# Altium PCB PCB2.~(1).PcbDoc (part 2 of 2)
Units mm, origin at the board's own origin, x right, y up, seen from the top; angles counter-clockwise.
Board outline 200 x 180 mm, 2 copper layers (Top Layer, Bottom Layer); 324 components, 291 nets, 661 pads, 0 vias.

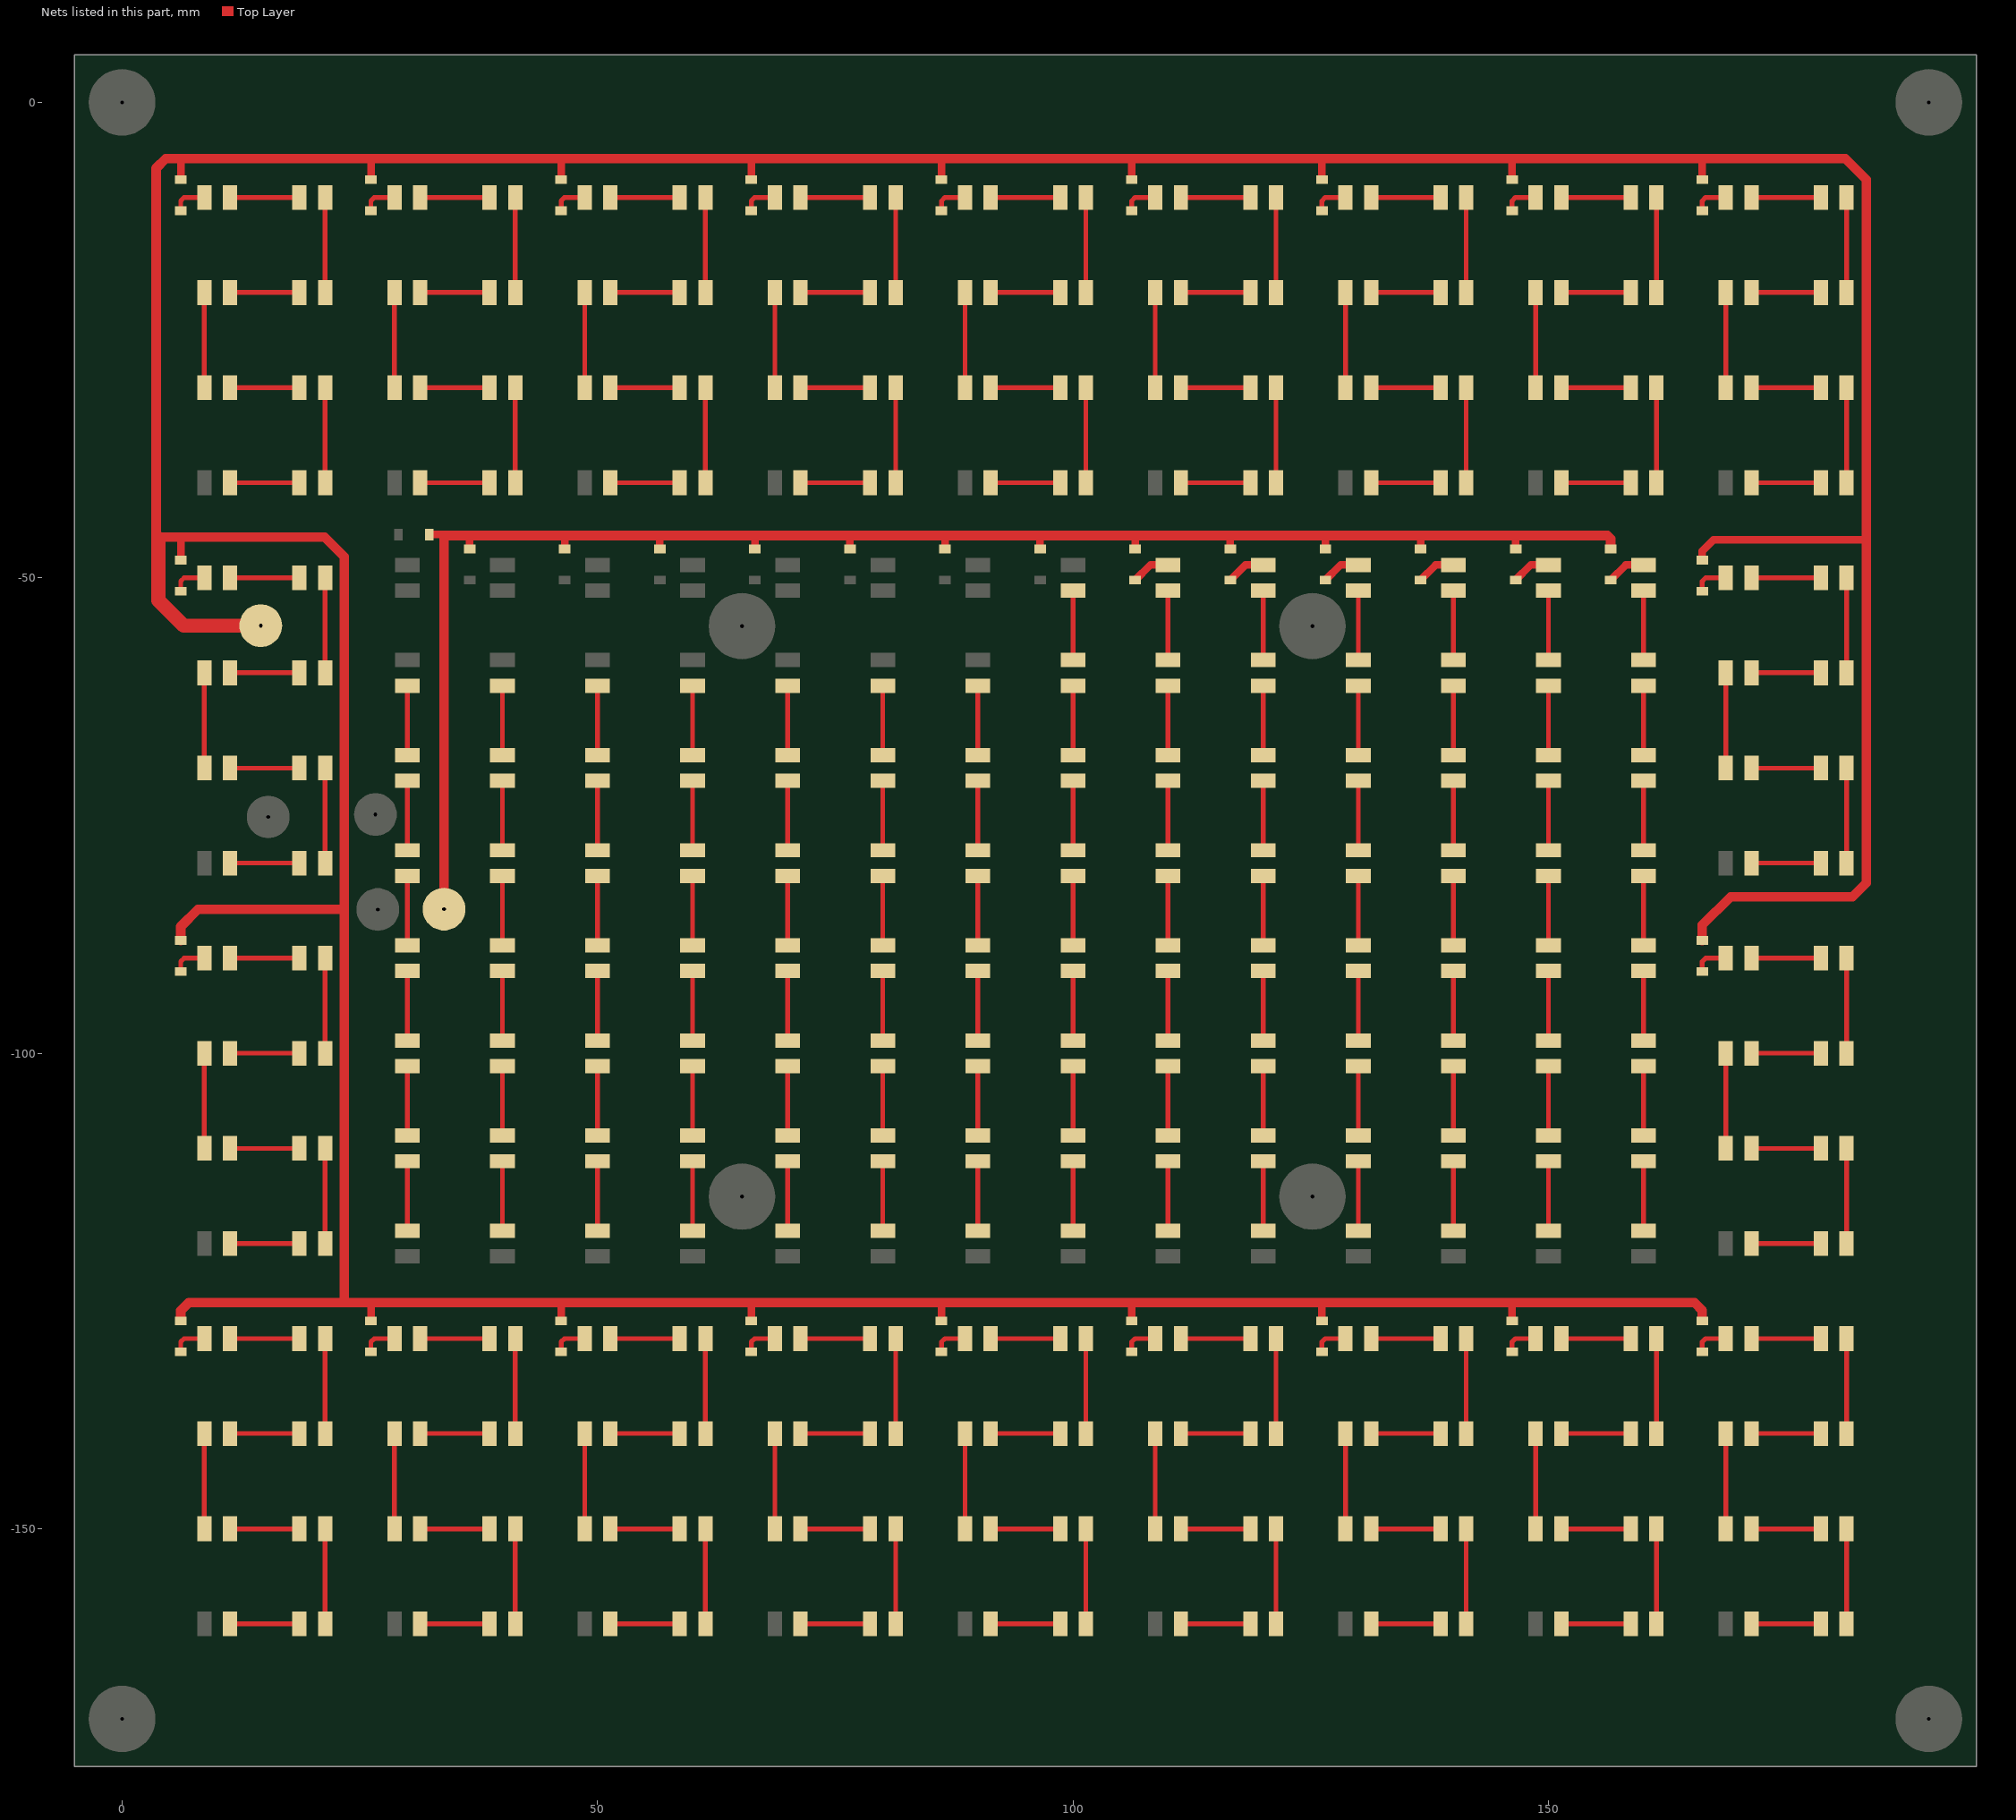
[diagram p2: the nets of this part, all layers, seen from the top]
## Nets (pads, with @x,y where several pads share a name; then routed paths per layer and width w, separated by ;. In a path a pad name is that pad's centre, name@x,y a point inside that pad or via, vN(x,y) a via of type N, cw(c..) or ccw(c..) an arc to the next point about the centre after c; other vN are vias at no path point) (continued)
NetD1_8_2: D1_8.2 D2_8.1 | length 7.3
  Top Layer w0.5: D2_8.1@100,-58.65 99.996,-58.65 99.996,-51.35 D1_8.2@100,-51.35
NetD1_9_1: D1_9.1 DR1_9.K | length 4.3
  Top Layer w0.8: DR1_9.K@106.546,-50.238 108.13,-48.654 D1_9.1@110.178,-48.654
NetD1_9_2: D1_9.2 D2_9.1 | length 7.3
  Top Layer w0.5: D2_9.1@110,-58.65 109.996,-58.65 109.996,-51.35 D1_9.2@110,-51.35
NetD1_10_1: D1_10.1 DR1_10.K | length 4.3
  Top Layer w0.8: DR1_10.K@116.546,-50.238 118.13,-48.654 D1_10.1@120.178,-48.654
NetD1_10_2: D1_10.2 D2_10.1 | length 7.3
  Top Layer w0.5: D2_10.1@120,-58.65 119.996,-58.65 119.996,-51.35 D1_10.2@120,-51.35
NetD1_11_1: D1_11.1 DR1_11.K | length 4.3
  Top Layer w0.8: DR1_11.K@126.546,-50.238 128.13,-48.654 D1_11.1@130.178,-48.654
NetD1_11_2: D1_11.2 D2_11.1 | length 7.3
  Top Layer w0.5: D2_11.1@130,-58.65 129.996,-58.65 129.996,-51.35 D1_11.2@130,-51.35
NetD1_12_1: D1_12.1 DR1_12.K | length 4.3
  Top Layer w0.8: DR1_12.K@136.546,-50.238 138.13,-48.654 D1_12.1@140.178,-48.654
NetD1_12_2: D1_12.2 D2_12.1 | length 7.3
  Top Layer w0.5: D2_12.1@140,-58.65 139.996,-58.65 139.996,-51.35 D1_12.2@140,-51.35
NetD1_13_1: D1_13.1 DR1_13.K | length 4.3
  Top Layer w0.8: DR1_13.K@146.546,-50.238 148.13,-48.654 D1_13.1@150.178,-48.654
NetD1_13_2: D1_13.2 D2_13.1 | length 7.3
  Top Layer w0.5: D2_13.1@150,-58.65 149.996,-58.65 149.996,-51.35 D1_13.2@150,-51.35
NetD1_14_1: D1_14.1 DR1_14.K | length 4.3
  Top Layer w0.8: DR1_14.K@156.546,-50.238 158.13,-48.654 D1_14.1@160.178,-48.654
NetD1_14_2: D1_14.2 D2_14.1 | length 7.3
  Top Layer w0.5: D2_14.1@160,-58.65 159.996,-58.65 159.996,-51.35 D1_14.2@160,-51.35
NetD1_15_1: D1_15.1 DR1_15.K | length 3.7
  Top Layer w0.5: DR1_15.K@6.175,-11.401 6.175,-10.351 6.525,-10 D1_15.1@8.65,-10
NetD1_15_2: D1_15.2 D2_15.1 | length 7.3
  Top Layer w0.5: D1_15.2@11.35,-10 D2_15.1@18.65,-10
NetD1_16_1: D1_16.1 DR1_16.K | length 3.7
  Top Layer w0.5: DR1_16.K@6.175,-51.401 6.175,-50.351 6.525,-50 D1_16.1@8.65,-50
NetD1_16_2: D1_16.2 D2_16.1 | length 7.3
  Top Layer w0.5: D1_16.2@11.35,-50 D2_16.1@18.65,-50
NetD1_17_1: D1_17.1 DR1_17.K | length 3.7
  Top Layer w0.5: DR1_17.K@6.175,-91.401 6.175,-90.351 6.525,-90 D1_17.1@8.65,-90
NetD1_17_2: D1_17.2 D2_17.1 | length 7.3
  Top Layer w0.5: D1_17.2@11.35,-90 D2_17.1@18.65,-90
NetD1_18_1: D1_18.1 DR1_18.K | length 3.7
  Top Layer w0.5: DR1_18.K@6.175,-131.401 6.175,-130.351 6.525,-130 D1_18.1@8.65,-130
NetD1_18_2: D1_18.2 D2_18.1 | length 7.3
  Top Layer w0.5: D1_18.2@11.35,-130 D2_18.1@18.65,-130
NetD1_19_1: D1_19.1 DR1_19.K | length 3.7
  Top Layer w0.5: DR1_19.K@26.175,-11.401 26.175,-10.351 26.525,-10 D1_19.1@28.65,-10
NetD1_19_2: D1_19.2 D2_19.1 | length 7.3
  Top Layer w0.5: D1_19.2@31.35,-10 D2_19.1@38.65,-10
NetD1_20_1: D1_20.1 DR1_20.K | length 3.7
  Top Layer w0.5: DR1_20.K@46.175,-11.401 46.175,-10.351 46.525,-10 D1_20.1@48.65,-10
NetD1_20_2: D1_20.2 D2_20.1 | length 7.3
  Top Layer w0.5: D1_20.2@51.35,-10 D2_20.1@58.65,-10
NetD1_21_1: D1_21.1 DR1_21.K | length 3.7
  Top Layer w0.5: DR1_21.K@66.175,-11.401 66.175,-10.351 66.525,-10 D1_21.1@68.65,-10
NetD1_21_2: D1_21.2 D2_21.1 | length 7.3
  Top Layer w0.5: D1_21.2@71.35,-10 D2_21.1@78.65,-10
NetD1_22_1: D1_22.1 DR1_22.K | length 3.7
  Top Layer w0.5: DR1_22.K@86.175,-11.401 86.175,-10.351 86.525,-10 D1_22.1@88.65,-10
NetD1_22_2: D1_22.2 D2_22.1 | length 7.3
  Top Layer w0.5: D1_22.2@91.35,-10 D2_22.1@98.65,-10
NetD1_23_1: D1_23.1 DR1_23.K | length 3.7
  Top Layer w0.5: DR1_23.K@106.175,-11.401 106.175,-10.351 106.525,-10 D1_23.1@108.65,-10
NetD1_23_2: D1_23.2 D2_23.1 | length 7.3
  Top Layer w0.5: D1_23.2@111.35,-10 D2_23.1@118.65,-10
NetD1_24_1: D1_24.1 DR1_24.K | length 3.7
  Top Layer w0.5: DR1_24.K@126.175,-11.401 126.175,-10.351 126.525,-10 D1_24.1@128.65,-10
NetD1_24_2: D1_24.2 D2_24.1 | length 7.3
  Top Layer w0.5: D1_24.2@131.35,-10 D2_24.1@138.65,-10
NetD1_25_1: D1_25.1 DR1_25.K | length 3.7
  Top Layer w0.5: DR1_25.K@146.175,-11.401 146.175,-10.351 146.525,-10 D1_25.1@148.65,-10
NetD1_25_2: D1_25.2 D2_25.1 | length 7.3
  Top Layer w0.5: D1_25.2@151.35,-10 D2_25.1@158.65,-10
NetD1_26_1: D1_26.1 DR1_26.K | length 3.7
  Top Layer w0.5: DR1_26.K@26.175,-131.401 26.175,-130.351 26.525,-130 D1_26.1@28.65,-130
NetD1_26_2: D1_26.2 D2_26.1 | length 7.3
  Top Layer w0.5: D1_26.2@31.35,-130 D2_26.1@38.65,-130
NetD1_27_1: D1_27.1 DR1_27.K | length 3.7
  Top Layer w0.5: DR1_27.K@46.175,-131.401 46.175,-130.351 46.525,-130 D1_27.1@48.65,-130
NetD1_27_2: D1_27.2 D2_27.1 | length 7.3
  Top Layer w0.5: D1_27.2@51.35,-130 D2_27.1@58.65,-130
NetD1_28_1: D1_28.1 DR1_28.K | length 3.7
  Top Layer w0.5: DR1_28.K@66.175,-131.401 66.175,-130.351 66.525,-130 D1_28.1@68.65,-130
NetD1_28_2: D1_28.2 D2_28.1 | length 7.3
  Top Layer w0.5: D1_28.2@71.35,-130 D2_28.1@78.65,-130
NetD1_29_1: D1_29.1 DR1_29.K | length 3.7
  Top Layer w0.5: DR1_29.K@86.175,-131.401 86.175,-130.351 86.525,-130 D1_29.1@88.65,-130
NetD1_29_2: D1_29.2 D2_29.1 | length 7.3
  Top Layer w0.5: D1_29.2@91.35,-130 D2_29.1@98.65,-130
NetD1_30_1: D1_30.1 DR1_30.K | length 3.7
  Top Layer w0.5: DR1_30.K@106.175,-131.401 106.175,-130.351 106.525,-130 D1_30.1@108.65,-130
NetD1_30_2: D1_30.2 D2_30.1 | length 7.3
  Top Layer w0.5: D1_30.2@111.35,-130 D2_30.1@118.65,-130
NetD1_31_1: D1_31.1 DR1_31.K | length 3.7
  Top Layer w0.5: DR1_31.K@126.175,-131.401 126.175,-130.351 126.525,-130 D1_31.1@128.65,-130
NetD1_31_2: D1_31.2 D2_31.1 | length 7.3
  Top Layer w0.5: D1_31.2@131.35,-130 D2_31.1@138.65,-130
NetD1_32_1: D1_32.1 DR1_32.K | length 3.7
  Top Layer w0.5: DR1_32.K@146.175,-131.401 146.175,-130.351 146.525,-130 D1_32.1@148.65,-130
NetD1_32_2: D1_32.2 D2_32.1 | length 7.3
  Top Layer w0.5: D1_32.2@151.35,-130 D2_32.1@158.65,-130
NetD1_33_1: D1_33.1 DR1_33.K | length 3.7
  Top Layer w0.5: DR1_33.K@166.175,-11.401 166.175,-10.351 166.525,-10 D1_33.1@168.65,-10
NetD1_33_2: D1_33.2 D2_33.1 | length 7.3
  Top Layer w0.5: D1_33.2@171.35,-10 D2_33.1@178.65,-10
NetD1_34_1: D1_34.1 DR1_34.K | length 3.7
  Top Layer w0.5: DR1_34.K@166.175,-51.401 166.175,-50.351 166.525,-50 D1_34.1@168.65,-50
NetD1_34_2: D1_34.2 D2_34.1 | length 7.3
  Top Layer w0.5: D1_34.2@171.35,-50 D2_34.1@178.65,-50
NetD1_35_1: D1_35.1 DR1_35.K | length 3.7
  Top Layer w0.5: DR1_35.K@166.175,-91.401 166.175,-90.351 166.525,-90 D1_35.1@168.65,-90
NetD1_35_2: D1_35.2 D2_35.1 | length 7.3
  Top Layer w0.5: D1_35.2@171.35,-90 D2_35.1@178.65,-90
NetD1_36_1: D1_36.1 DR1_36.K | length 3.7
  Top Layer w0.5: DR1_36.K@166.175,-131.401 166.175,-130.351 166.525,-130 D1_36.1@168.65,-130
NetD1_36_2: D1_36.2 D2_36.1 | length 7.3
  Top Layer w0.5: D1_36.2@171.35,-130 D2_36.1@178.65,-130
NetD2_1_2: D2_1.2 D3_1.1 | length 7.3
  Top Layer w0.5: D3_1.1@30,-68.65 29.996,-68.65 29.996,-61.35 D2_1.2@30,-61.35
NetD2_2_2: D2_2.2 D3_2.1 | length 7.3
  Top Layer w0.5: D3_2.1@40,-68.65 39.996,-68.65 39.996,-61.35 D2_2.2@40,-61.35
NetD2_3_2: D2_3.2 D3_3.1 | length 7.3
  Top Layer w0.5: D3_3.1@50,-68.65 49.996,-68.65 49.996,-61.35 D2_3.2@50,-61.35
NetD2_4_2: D2_4.2 D3_4.1 | length 7.3
  Top Layer w0.5: D3_4.1@60,-68.65 59.996,-68.65 59.996,-61.35 D2_4.2@60,-61.35
NetD2_5_2: D2_5.2 D3_5.1 | length 7.3
  Top Layer w0.5: D3_5.1@70,-68.65 69.996,-68.65 69.996,-61.35 D2_5.2@70,-61.35
NetD2_6_2: D2_6.2 D3_6.1 | length 7.3
  Top Layer w0.5: D3_6.1@80,-68.65 79.996,-68.65 79.996,-61.35 D2_6.2@80,-61.35
NetD2_7_2: D2_7.2 D3_7.1 | length 7.3
  Top Layer w0.5: D3_7.1@90,-68.65 89.996,-68.65 89.996,-61.35 D2_7.2@90,-61.35
NetD2_8_2: D2_8.2 D3_8.1 | length 7.3
  Top Layer w0.5: D3_8.1@100,-68.65 99.996,-68.65 99.996,-61.35 D2_8.2@100,-61.35
NetD2_9_2: D2_9.2 D3_9.1 | length 7.3
  Top Layer w0.5: D3_9.1@110,-68.65 109.996,-68.65 109.996,-61.35 D2_9.2@110,-61.35
NetD2_10_2: D2_10.2 D3_10.1 | length 7.3
  Top Layer w0.5: D3_10.1@120,-68.65 119.996,-68.65 119.996,-61.35 D2_10.2@120,-61.35
NetD2_11_2: D2_11.2 D3_11.1 | length 7.3
  Top Layer w0.5: D3_11.1@130,-68.65 129.996,-68.65 129.996,-61.35 D2_11.2@130,-61.35
NetD2_12_2: D2_12.2 D3_12.1 | length 7.3
  Top Layer w0.5: D3_12.1@140,-68.65 139.996,-68.65 139.996,-61.35 D2_12.2@140,-61.35
NetD2_13_2: D2_13.2 D3_13.1 | length 7.3
  Top Layer w0.5: D3_13.1@150,-68.65 149.996,-68.65 149.996,-61.35 D2_13.2@150,-61.35
NetD2_14_2: D2_14.2 D3_14.1 | length 7.3
  Top Layer w0.5: D3_14.1@160,-68.65 159.996,-68.65 159.996,-61.35 D2_14.2@160,-61.35
NetD2_15_2: D2_15.2 D3_15.1 | length 10
  Top Layer w0.5: D3_15.1@21.35,-20 D2_15.2@21.35,-10
NetD2_16_2: D2_16.2 D3_16.1 | length 10
  Top Layer w0.5: D3_16.1@21.35,-60 D2_16.2@21.35,-50
NetD2_17_2: D2_17.2 D3_17.1 | length 10
  Top Layer w0.5: D3_17.1@21.35,-100 D2_17.2@21.35,-90
NetD2_18_2: D2_18.2 D3_18.1 | length 10
  Top Layer w0.5: D3_18.1@21.35,-140 D2_18.2@21.35,-130
NetD2_19_2: D2_19.2 D3_19.1 | length 10
  Top Layer w0.5: D3_19.1@41.35,-20 D2_19.2@41.35,-10
NetD2_20_2: D2_20.2 D3_20.1 | length 10
  Top Layer w0.5: D3_20.1@61.35,-20 D2_20.2@61.35,-10
NetD2_21_2: D2_21.2 D3_21.1 | length 10
  Top Layer w0.5: D3_21.1@81.35,-20 D2_21.2@81.35,-10
NetD2_22_2: D2_22.2 D3_22.1 | length 10
  Top Layer w0.5: D3_22.1@101.35,-20 D2_22.2@101.35,-10
NetD2_23_2: D2_23.2 D3_23.1 | length 10
  Top Layer w0.5: D3_23.1@121.35,-20 D2_23.2@121.35,-10
NetD2_24_2: D2_24.2 D3_24.1 | length 10
  Top Layer w0.5: D3_24.1@141.35,-20 D2_24.2@141.35,-10
NetD2_25_2: D2_25.2 D3_25.1 | length 10
  Top Layer w0.5: D3_25.1@161.35,-20 D2_25.2@161.35,-10
NetD2_26_2: D2_26.2 D3_26.1 | length 10
  Top Layer w0.5: D3_26.1@41.35,-140 D2_26.2@41.35,-130
NetD2_27_2: D2_27.2 D3_27.1 | length 10
  Top Layer w0.5: D3_27.1@61.35,-140 D2_27.2@61.35,-130
NetD2_28_2: D2_28.2 D3_28.1 | length 10
  Top Layer w0.5: D3_28.1@81.35,-140 D2_28.2@81.35,-130
NetD2_29_2: D2_29.2 D3_29.1 | length 10
  Top Layer w0.5: D3_29.1@101.35,-140 D2_29.2@101.35,-130
NetD2_30_2: D2_30.2 D3_30.1 | length 10
  Top Layer w0.5: D3_30.1@121.35,-140 D2_30.2@121.35,-130
NetD2_31_2: D2_31.2 D3_31.1 | length 10
  Top Layer w0.5: D3_31.1@141.35,-140 D2_31.2@141.35,-130
NetD2_32_2: D2_32.2 D3_32.1 | length 10
  Top Layer w0.5: D3_32.1@161.35,-140 D2_32.2@161.35,-130
NetD2_33_2: D2_33.2 D3_33.1 | length 10
  Top Layer w0.5: D3_33.1@181.35,-20 D2_33.2@181.35,-10
NetD2_34_2: D2_34.2 D3_34.1 | length 10
  Top Layer w0.5: D3_34.1@181.35,-60 D2_34.2@181.35,-50
NetD2_35_2: D2_35.2 D3_35.1 | length 10
  Top Layer w0.5: D3_35.1@181.35,-100 D2_35.2@181.35,-90
NetD2_36_2: D2_36.2 D3_36.1 | length 10
  Top Layer w0.5: D3_36.1@181.35,-140 D2_36.2@181.35,-130
NetD3_1_2: D3_1.2 D4_1.1 | length 7.3
  Top Layer w0.5: D4_1.1@30,-78.65 29.996,-78.65 29.996,-71.35 D3_1.2@30,-71.35
NetD3_2_2: D3_2.2 D4_2.1 | length 7.3
  Top Layer w0.5: D4_2.1@40,-78.65 39.996,-78.65 39.996,-71.35 D3_2.2@40,-71.35
NetD3_3_2: D3_3.2 D4_3.1 | length 7.3
  Top Layer w0.5: D4_3.1@50,-78.65 49.996,-78.65 49.996,-71.35 D3_3.2@50,-71.35
NetD3_4_2: D3_4.2 D4_4.1 | length 7.3
  Top Layer w0.5: D4_4.1@60,-78.65 59.996,-78.65 59.996,-71.35 D3_4.2@60,-71.35
NetD3_5_2: D3_5.2 D4_5.1 | length 7.3
  Top Layer w0.5: D4_5.1@70,-78.65 69.996,-78.65 69.996,-71.35 D3_5.2@70,-71.35
NetD3_6_2: D3_6.2 D4_6.1 | length 7.3
  Top Layer w0.5: D4_6.1@80,-78.65 79.996,-78.65 79.996,-71.35 D3_6.2@80,-71.35
NetD3_7_2: D3_7.2 D4_7.1 | length 7.3
  Top Layer w0.5: D4_7.1@90,-78.65 89.996,-78.65 89.996,-71.35 D3_7.2@90,-71.35
NetD3_8_2: D3_8.2 D4_8.1 | length 7.3
  Top Layer w0.5: D4_8.1@100,-78.65 99.996,-78.65 99.996,-71.35 D3_8.2@100,-71.35
NetD3_9_2: D3_9.2 D4_9.1 | length 7.3
  Top Layer w0.5: D4_9.1@110,-78.65 109.996,-78.65 109.996,-71.35 D3_9.2@110,-71.35
NetD3_10_2: D3_10.2 D4_10.1 | length 7.3
  Top Layer w0.5: D4_10.1@120,-78.65 119.996,-78.65 119.996,-71.35 D3_10.2@120,-71.35
NetD3_11_2: D3_11.2 D4_11.1 | length 7.3
  Top Layer w0.5: D4_11.1@130,-78.65 129.996,-78.65 129.996,-71.35 D3_11.2@130,-71.35
NetD3_12_2: D3_12.2 D4_12.1 | length 7.3
  Top Layer w0.5: D4_12.1@140,-78.65 139.996,-78.65 139.996,-71.35 D3_12.2@140,-71.35
NetD3_13_2: D3_13.2 D4_13.1 | length 7.3
  Top Layer w0.5: D4_13.1@150,-78.65 149.996,-78.65 149.996,-71.35 D3_13.2@150,-71.35
NetD3_14_2: D3_14.2 D4_14.1 | length 7.3
  Top Layer w0.5: D4_14.1@160,-78.65 159.996,-78.65 159.996,-71.35 D3_14.2@160,-71.35
NetD3_15_2: D3_15.2 D4_15.1 | length 7.3
  Top Layer w0.5: D4_15.1@11.35,-20 11.35,-19.983 18.65,-19.983 D3_15.2@18.65,-20
NetD3_16_2: D3_16.2 D4_16.1 | length 7.3
  Top Layer w0.5: D4_16.1@11.35,-60 11.35,-59.983 18.65,-59.983 D3_16.2@18.65,-60
NetD3_17_2: D3_17.2 D4_17.1 | length 7.3
  Top Layer w0.5: D4_17.1@11.35,-100 11.35,-99.983 18.65,-99.983 D3_17.2@18.65,-100
NetD3_18_2: D3_18.2 D4_18.1 | length 7.3
  Top Layer w0.5: D4_18.1@11.35,-140 11.35,-139.983 18.65,-139.983 D3_18.2@18.65,-140
NetD3_19_2: D3_19.2 D4_19.1 | length 7.3
  Top Layer w0.5: D4_19.1@31.35,-20 31.35,-19.983 38.65,-19.983 D3_19.2@38.65,-20
NetD3_20_2: D3_20.2 D4_20.1 | length 7.3
  Top Layer w0.5: D4_20.1@51.35,-20 51.35,-19.983 58.65,-19.983 D3_20.2@58.65,-20
NetD3_21_2: D3_21.2 D4_21.1 | length 7.3
  Top Layer w0.5: D4_21.1@71.35,-20 71.35,-19.983 78.65,-19.983 D3_21.2@78.65,-20
NetD3_22_2: D3_22.2 D4_22.1 | length 7.3
  Top Layer w0.5: D4_22.1@91.35,-20 91.35,-19.983 98.65,-19.983 D3_22.2@98.65,-20
NetD3_23_2: D3_23.2 D4_23.1 | length 7.3
  Top Layer w0.5: D4_23.1@111.35,-20 111.35,-19.983 118.65,-19.983 D3_23.2@118.65,-20
NetD3_24_2: D3_24.2 D4_24.1 | length 7.3
  Top Layer w0.5: D4_24.1@131.35,-20 131.35,-19.983 138.65,-19.983 D3_24.2@138.65,-20
NetD3_25_2: D3_25.2 D4_25.1 | length 7.3
  Top Layer w0.5: D4_25.1@151.35,-20 151.35,-19.983 158.65,-19.983 D3_25.2@158.65,-20
NetD3_26_2: D3_26.2 D4_26.1 | length 7.3
  Top Layer w0.5: D4_26.1@31.35,-140 31.35,-139.983 38.65,-139.983 D3_26.2@38.65,-140
NetD3_27_2: D3_27.2 D4_27.1 | length 7.3
  Top Layer w0.5: D4_27.1@51.35,-140 51.35,-139.983 58.65,-139.983 D3_27.2@58.65,-140
NetD3_28_2: D3_28.2 D4_28.1 | length 7.3
  Top Layer w0.5: D4_28.1@71.35,-140 71.35,-139.983 78.65,-139.983 D3_28.2@78.65,-140
NetD3_29_2: D3_29.2 D4_29.1 | length 7.3
  Top Layer w0.5: D4_29.1@91.35,-140 91.35,-139.983 98.65,-139.983 D3_29.2@98.65,-140
NetD3_30_2: D3_30.2 D4_30.1 | length 7.3
  Top Layer w0.5: D4_30.1@111.35,-140 111.35,-139.983 118.65,-139.983 D3_30.2@118.65,-140
NetD3_31_2: D3_31.2 D4_31.1 | length 7.3
  Top Layer w0.5: D4_31.1@131.35,-140 131.35,-139.983 138.65,-139.983 D3_31.2@138.65,-140
NetD3_32_2: D3_32.2 D4_32.1 | length 7.3
  Top Layer w0.5: D4_32.1@151.35,-140 151.35,-139.983 158.65,-139.983 D3_32.2@158.65,-140
NetD3_33_2: D3_33.2 D4_33.1 | length 7.3
  Top Layer w0.5: D4_33.1@171.35,-20 171.35,-19.983 178.65,-19.983 D3_33.2@178.65,-20
NetD3_34_2: D3_34.2 D4_34.1 | length 7.3
  Top Layer w0.5: D4_34.1@171.35,-60 171.35,-59.983 178.65,-59.983 D3_34.2@178.65,-60
NetD3_35_2: D3_35.2 D4_35.1 | length 7.3
  Top Layer w0.5: D4_35.1@171.35,-100 171.35,-99.983 178.65,-99.983 D3_35.2@178.65,-100
NetD3_36_2: D3_36.2 D4_36.1 | length 7.3
  Top Layer w0.5: D4_36.1@171.35,-140 171.35,-139.983 178.65,-139.983 D3_36.2@178.65,-140
NetD4_1_2: D4_1.2 D5_1.1 | length 7.3
  Top Layer w0.5: D5_1.1@30,-88.65 29.996,-88.65 29.996,-81.35 D4_1.2@30,-81.35
NetD4_2_2: D4_2.2 D5_2.1 | length 7.3
  Top Layer w0.5: D5_2.1@40,-88.65 39.996,-88.65 39.996,-81.35 D4_2.2@40,-81.35
NetD4_3_2: D4_3.2 D5_3.1 | length 7.3
  Top Layer w0.5: D5_3.1@50,-88.65 49.996,-88.65 49.996,-81.35 D4_3.2@50,-81.35
NetD4_4_2: D4_4.2 D5_4.1 | length 7.3
  Top Layer w0.5: D5_4.1@60,-88.65 59.996,-88.65 59.996,-81.35 D4_4.2@60,-81.35
NetD4_5_2: D4_5.2 D5_5.1 | length 7.3
  Top Layer w0.5: D5_5.1@70,-88.65 69.996,-88.65 69.996,-81.35 D4_5.2@70,-81.35
NetD4_6_2: D4_6.2 D5_6.1 | length 7.3
  Top Layer w0.5: D5_6.1@80,-88.65 79.996,-88.65 79.996,-81.35 D4_6.2@80,-81.35
NetD4_7_2: D4_7.2 D5_7.1 | length 7.3
  Top Layer w0.5: D5_7.1@90,-88.65 89.996,-88.65 89.996,-81.35 D4_7.2@90,-81.35
NetD4_8_2: D4_8.2 D5_8.1 | length 7.3
  Top Layer w0.5: D5_8.1@100,-88.65 99.996,-88.65 99.996,-81.35 D4_8.2@100,-81.35
NetD4_9_2: D4_9.2 D5_9.1 | length 7.3
  Top Layer w0.5: D5_9.1@110,-88.65 109.996,-88.65 109.996,-81.35 D4_9.2@110,-81.35
NetD4_10_2: D4_10.2 D5_10.1 | length 7.3
  Top Layer w0.5: D5_10.1@120,-88.65 119.996,-88.65 119.996,-81.35 D4_10.2@120,-81.35
NetD4_11_2: D4_11.2 D5_11.1 | length 7.3
  Top Layer w0.5: D5_11.1@130,-88.65 129.996,-88.65 129.996,-81.35 D4_11.2@130,-81.35
NetD4_12_2: D4_12.2 D5_12.1 | length 7.3
  Top Layer w0.5: D5_12.1@140,-88.65 139.996,-88.65 139.996,-81.35 D4_12.2@140,-81.35
NetD4_13_2: D4_13.2 D5_13.1 | length 7.3
  Top Layer w0.5: D5_13.1@150,-88.65 149.996,-88.65 149.996,-81.35 D4_13.2@150,-81.35
NetD4_14_2: D4_14.2 D5_14.1 | length 7.3
  Top Layer w0.5: D5_14.1@160,-88.65 159.996,-88.65 159.996,-81.35 D4_14.2@160,-81.35
NetD4_15_2: D4_15.2 D5_15.1 | length 10
  Top Layer w0.5: D5_15.1@8.65,-30 D4_15.2@8.65,-20
NetD4_16_2: D4_16.2 D5_16.1 | length 10
  Top Layer w0.5: D5_16.1@8.65,-70 D4_16.2@8.65,-60
NetD4_17_2: D4_17.2 D5_17.1 | length 10
  Top Layer w0.5: D5_17.1@8.65,-110 D4_17.2@8.65,-100
NetD4_18_2: D4_18.2 D5_18.1 | length 10
  Top Layer w0.5: D5_18.1@8.65,-150 D4_18.2@8.65,-140
NetD4_19_2: D4_19.2 D5_19.1 | length 10
  Top Layer w0.5: D5_19.1@28.65,-30 D4_19.2@28.65,-20
NetD4_20_2: D4_20.2 D5_20.1 | length 10
  Top Layer w0.5: D5_20.1@48.65,-30 D4_20.2@48.65,-20
NetD4_21_2: D4_21.2 D5_21.1 | length 10
  Top Layer w0.5: D5_21.1@68.65,-30 D4_21.2@68.65,-20
NetD4_22_2: D4_22.2 D5_22.1 | length 10
  Top Layer w0.5: D5_22.1@88.65,-30 D4_22.2@88.65,-20
NetD4_23_2: D4_23.2 D5_23.1 | length 10
  Top Layer w0.5: D5_23.1@108.65,-30 D4_23.2@108.65,-20
NetD4_24_2: D4_24.2 D5_24.1 | length 10
  Top Layer w0.5: D5_24.1@128.65,-30 D4_24.2@128.65,-20
NetD4_25_2: D4_25.2 D5_25.1 | length 10
  Top Layer w0.5: D5_25.1@148.65,-30 D4_25.2@148.65,-20
NetD4_26_2: D4_26.2 D5_26.1 | length 10
  Top Layer w0.5: D5_26.1@28.65,-150 D4_26.2@28.65,-140
NetD4_27_2: D4_27.2 D5_27.1 | length 10
  Top Layer w0.5: D5_27.1@48.65,-150 D4_27.2@48.65,-140
NetD4_28_2: D4_28.2 D5_28.1 | length 10
  Top Layer w0.5: D5_28.1@68.65,-150 D4_28.2@68.65,-140
NetD4_29_2: D4_29.2 D5_29.1 | length 10
  Top Layer w0.5: D5_29.1@88.65,-150 D4_29.2@88.65,-140
NetD4_30_2: D4_30.2 D5_30.1 | length 10
  Top Layer w0.5: D5_30.1@108.65,-150 D4_30.2@108.65,-140
NetD4_31_2: D4_31.2 D5_31.1 | length 10
  Top Layer w0.5: D5_31.1@128.65,-150 D4_31.2@128.65,-140
NetD4_32_2: D4_32.2 D5_32.1 | length 10
  Top Layer w0.5: D5_32.1@148.65,-150 D4_32.2@148.65,-140
NetD4_33_2: D4_33.2 D5_33.1 | length 10
  Top Layer w0.5: D5_33.1@168.65,-30 D4_33.2@168.65,-20
NetD4_34_2: D4_34.2 D5_34.1 | length 10
  Top Layer w0.5: D5_34.1@168.65,-70 D4_34.2@168.65,-60
NetD4_35_2: D4_35.2 D5_35.1 | length 10
  Top Layer w0.5: D5_35.1@168.65,-110 D4_35.2@168.65,-100
NetD4_36_2: D4_36.2 D5_36.1 | length 10
  Top Layer w0.5: D5_36.1@168.65,-150 D4_36.2@168.65,-140
NetD5_1_2: D5_1.2 D6_1.1 | length 7.3
  Top Layer w0.5: D6_1.1@30,-98.65 29.996,-98.65 29.996,-91.35 D5_1.2@30,-91.35
NetD5_2_2: D5_2.2 D6_2.1 | length 7.3
  Top Layer w0.5: D6_2.1@40,-98.65 39.996,-98.65 39.996,-91.35 D5_2.2@40,-91.35
NetD5_3_2: D5_3.2 D6_3.1 | length 7.3
  Top Layer w0.5: D6_3.1@50,-98.65 49.996,-98.65 49.996,-91.35 D5_3.2@50,-91.35
NetD5_4_2: D5_4.2 D6_4.1 | length 7.3
  Top Layer w0.5: D6_4.1@60,-98.65 59.996,-98.65 59.996,-91.35 D5_4.2@60,-91.35
NetD5_5_2: D5_5.2 D6_5.1 | length 7.3
  Top Layer w0.5: D6_5.1@70,-98.65 69.996,-98.65 69.996,-91.35 D5_5.2@70,-91.35
NetD5_6_2: D5_6.2 D6_6.1 | length 7.3
  Top Layer w0.5: D6_6.1@80,-98.65 79.996,-98.65 79.996,-91.35 D5_6.2@80,-91.35
NetD5_7_2: D5_7.2 D6_7.1 | length 7.3
  Top Layer w0.5: D6_7.1@90,-98.65 89.996,-98.65 89.996,-91.35 D5_7.2@90,-91.35
NetD5_8_2: D5_8.2 D6_8.1 | length 7.3
  Top Layer w0.5: D6_8.1@100,-98.65 99.996,-98.65 99.996,-91.35 D5_8.2@100,-91.35
NetD5_9_2: D5_9.2 D6_9.1 | length 7.3
  Top Layer w0.5: D6_9.1@110,-98.65 109.996,-98.65 109.996,-91.35 D5_9.2@110,-91.35
NetD5_10_2: D5_10.2 D6_10.1 | length 7.3
  Top Layer w0.5: D6_10.1@120,-98.65 119.996,-98.65 119.996,-91.35 D5_10.2@120,-91.35
NetD5_11_2: D5_11.2 D6_11.1 | length 7.3
  Top Layer w0.5: D6_11.1@130,-98.65 129.996,-98.65 129.996,-91.35 D5_11.2@130,-91.35
NetD5_12_2: D5_12.2 D6_12.1 | length 7.3
  Top Layer w0.5: D6_12.1@140,-98.65 139.996,-98.65 139.996,-91.35 D5_12.2@140,-91.35
NetD5_13_2: D5_13.2 D6_13.1 | length 7.3
  Top Layer w0.5: D6_13.1@150,-98.65 149.996,-98.65 149.996,-91.35 D5_13.2@150,-91.35
NetD5_14_2: D5_14.2 D6_14.1 | length 7.3
  Top Layer w0.5: D6_14.1@160,-98.65 159.996,-98.65 159.996,-91.35 D5_14.2@160,-91.35
NetD5_15_2: D5_15.2 D6_15.1 | length 7.3
  Top Layer w0.5: D5_15.2@11.35,-30 11.35,-30.016 18.65,-30.016 D6_15.1@18.65,-30
NetD5_16_2: D5_16.2 D6_16.1 | length 7.3
  Top Layer w0.5: D5_16.2@11.35,-70 11.35,-70.016 18.65,-70.016 D6_16.1@18.65,-70
NetD5_17_2: D5_17.2 D6_17.1 | length 7.3
  Top Layer w0.5: D5_17.2@11.35,-110 11.35,-110.016 18.65,-110.016 D6_17.1@18.65,-110
NetD5_18_2: D5_18.2 D6_18.1 | length 7.3
  Top Layer w0.5: D5_18.2@11.35,-150 11.35,-150.016 18.65,-150.016 D6_18.1@18.65,-150
NetD5_19_2: D5_19.2 D6_19.1 | length 7.3
  Top Layer w0.5: D5_19.2@31.35,-30 31.35,-30.016 38.65,-30.016 D6_19.1@38.65,-30
NetD5_20_2: D5_20.2 D6_20.1 | length 7.3
  Top Layer w0.5: D5_20.2@51.35,-30 51.35,-30.016 58.65,-30.016 D6_20.1@58.65,-30
NetD5_21_2: D5_21.2 D6_21.1 | length 7.3
  Top Layer w0.5: D5_21.2@71.35,-30 71.35,-30.016 78.65,-30.016 D6_21.1@78.65,-30
NetD5_22_2: D5_22.2 D6_22.1 | length 7.3
  Top Layer w0.5: D5_22.2@91.35,-30 91.35,-30.016 98.65,-30.016 D6_22.1@98.65,-30
NetD5_23_2: D5_23.2 D6_23.1 | length 7.3
  Top Layer w0.5: D5_23.2@111.35,-30 111.35,-30.016 118.65,-30.016 D6_23.1@118.65,-30
NetD5_24_2: D5_24.2 D6_24.1 | length 7.3
  Top Layer w0.5: D5_24.2@131.35,-30 131.35,-30.016 138.65,-30.016 D6_24.1@138.65,-30
NetD5_25_2: D5_25.2 D6_25.1 | length 7.3
  Top Layer w0.5: D5_25.2@151.35,-30 151.35,-30.016 158.65,-30.016 D6_25.1@158.65,-30
NetD5_26_2: D5_26.2 D6_26.1 | length 7.3
  Top Layer w0.5: D5_26.2@31.35,-150 31.35,-150.016 38.65,-150.016 D6_26.1@38.65,-150
NetD5_27_2: D5_27.2 D6_27.1 | length 7.3
  Top Layer w0.5: D5_27.2@51.35,-150 51.35,-150.016 58.65,-150.016 D6_27.1@58.65,-150
NetD5_28_2: D5_28.2 D6_28.1 | length 7.3
  Top Layer w0.5: D5_28.2@71.35,-150 71.35,-150.016 78.65,-150.016 D6_28.1@78.65,-150
NetD5_29_2: D5_29.2 D6_29.1 | length 7.3
  Top Layer w0.5: D5_29.2@91.35,-150 91.35,-150.016 98.65,-150.016 D6_29.1@98.65,-150
NetD5_30_2: D5_30.2 D6_30.1 | length 7.3
  Top Layer w0.5: D5_30.2@111.35,-150 111.35,-150.016 118.65,-150.016 D6_30.1@118.65,-150
NetD5_31_2: D5_31.2 D6_31.1 | length 7.3
  Top Layer w0.5: D5_31.2@131.35,-150 131.35,-150.016 138.65,-150.016 D6_31.1@138.65,-150
NetD5_32_2: D5_32.2 D6_32.1 | length 7.3
  Top Layer w0.5: D5_32.2@151.35,-150 151.35,-150.016 158.65,-150.016 D6_32.1@158.65,-150
NetD5_33_2: D5_33.2 D6_33.1 | length 7.3
  Top Layer w0.5: D5_33.2@171.35,-30 171.35,-30.016 178.65,-30.016 D6_33.1@178.65,-30
NetD5_34_2: D5_34.2 D6_34.1 | length 7.3
  Top Layer w0.5: D5_34.2@171.35,-70 171.35,-70.016 178.65,-70.016 D6_34.1@178.65,-70
NetD5_35_2: D5_35.2 D6_35.1 | length 7.3
  Top Layer w0.5: D5_35.2@171.35,-110 171.35,-110.016 178.65,-110.016 D6_35.1@178.65,-110
NetD5_36_2: D5_36.2 D6_36.1 | length 7.3
  Top Layer w0.5: D5_36.2@171.35,-150 171.35,-150.016 178.65,-150.016 D6_36.1@178.65,-150
NetD6_1_2: D6_1.2 D7_1.1 | length 7.3
  Top Layer w0.5: D7_1.1@30,-108.65 29.996,-108.65 29.996,-101.35 D6_1.2@30,-101.35
NetD6_2_2: D6_2.2 D7_2.1 | length 7.3
  Top Layer w0.5: D7_2.1@40,-108.65 39.996,-108.65 39.996,-101.35 D6_2.2@40,-101.35
NetD6_3_2: D6_3.2 D7_3.1 | length 7.3
  Top Layer w0.5: D7_3.1@50,-108.65 49.996,-108.65 49.996,-101.35 D6_3.2@50,-101.35
NetD6_4_2: D6_4.2 D7_4.1 | length 7.3
  Top Layer w0.5: D7_4.1@60,-108.65 59.996,-108.65 59.996,-101.35 D6_4.2@60,-101.35
NetD6_5_2: D6_5.2 D7_5.1 | length 7.3
  Top Layer w0.5: D7_5.1@70,-108.65 69.996,-108.65 69.996,-101.35 D6_5.2@70,-101.35
NetD6_6_2: D6_6.2 D7_6.1 | length 7.3
  Top Layer w0.5: D7_6.1@80,-108.65 79.996,-108.65 79.996,-101.35 D6_6.2@80,-101.35
NetD6_7_2: D6_7.2 D7_7.1 | length 7.3
  Top Layer w0.5: D7_7.1@90,-108.65 89.996,-108.65 89.996,-101.35 D6_7.2@90,-101.35
NetD6_8_2: D6_8.2 D7_8.1 | length 7.3
  Top Layer w0.5: D7_8.1@100,-108.65 99.996,-108.65 99.996,-101.35 D6_8.2@100,-101.35
NetD6_9_2: D6_9.2 D7_9.1 | length 7.3
  Top Layer w0.5: D7_9.1@110,-108.65 109.996,-108.65 109.996,-101.35 D6_9.2@110,-101.35
NetD6_10_2: D6_10.2 D7_10.1 | length 7.3
  Top Layer w0.5: D7_10.1@120,-108.65 119.996,-108.65 119.996,-101.35 D6_10.2@120,-101.35
NetD6_11_2: D6_11.2 D7_11.1 | length 7.3
  Top Layer w0.5: D7_11.1@130,-108.65 129.996,-108.65 129.996,-101.35 D6_11.2@130,-101.35
NetD6_12_2: D6_12.2 D7_12.1 | length 7.3
  Top Layer w0.5: D7_12.1@140,-108.65 139.996,-108.65 139.996,-101.35 D6_12.2@140,-101.35
NetD6_13_2: D6_13.2 D7_13.1 | length 7.3
  Top Layer w0.5: D7_13.1@150,-108.65 149.996,-108.65 149.996,-101.35 D6_13.2@150,-101.35
NetD6_14_2: D6_14.2 D7_14.1 | length 7.3
  Top Layer w0.5: D7_14.1@160,-108.65 159.996,-108.65 159.996,-101.35 D6_14.2@160,-101.35
NetD6_15_2: D6_15.2 D7_15.1 | length 10
  Top Layer w0.5: D7_15.1@21.35,-40 D6_15.2@21.35,-30
NetD6_16_2: D6_16.2 D7_16.1 | length 10
  Top Layer w0.5: D7_16.1@21.35,-80 D6_16.2@21.35,-70
NetD6_17_2: D6_17.2 D7_17.1 | length 10
  Top Layer w0.5: D7_17.1@21.35,-120 D6_17.2@21.35,-110
NetD6_18_2: D6_18.2 D7_18.1 | length 10
  Top Layer w0.5: D7_18.1@21.35,-160 D6_18.2@21.35,-150
NetD6_19_2: D6_19.2 D7_19.1 | length 10
  Top Layer w0.5: D7_19.1@41.35,-40 D6_19.2@41.35,-30
NetD6_20_2: D6_20.2 D7_20.1 | length 10
  Top Layer w0.5: D7_20.1@61.35,-40 D6_20.2@61.35,-30
NetD6_21_2: D6_21.2 D7_21.1 | length 10
  Top Layer w0.5: D7_21.1@81.35,-40 D6_21.2@81.35,-30
NetD6_22_2: D6_22.2 D7_22.1 | length 10
  Top Layer w0.5: D7_22.1@101.35,-40 D6_22.2@101.35,-30
NetD6_23_2: D6_23.2 D7_23.1 | length 10
  Top Layer w0.5: D7_23.1@121.35,-40 D6_23.2@121.35,-30
NetD6_24_2: D6_24.2 D7_24.1 | length 10
  Top Layer w0.5: D7_24.1@141.35,-40 D6_24.2@141.35,-30
NetD6_25_2: D6_25.2 D7_25.1 | length 10
  Top Layer w0.5: D7_25.1@161.35,-40 D6_25.2@161.35,-30
NetD6_26_2: D6_26.2 D7_26.1 | length 10
  Top Layer w0.5: D7_26.1@41.35,-160 D6_26.2@41.35,-150
NetD6_27_2: D6_27.2 D7_27.1 | length 10
  Top Layer w0.5: D7_27.1@61.35,-160 D6_27.2@61.35,-150
NetD6_28_2: D6_28.2 D7_28.1 | length 10
  Top Layer w0.5: D7_28.1@81.35,-160 D6_28.2@81.35,-150
NetD6_29_2: D6_29.2 D7_29.1 | length 10
  Top Layer w0.5: D7_29.1@101.35,-160 D6_29.2@101.35,-150
NetD6_30_2: D6_30.2 D7_30.1 | length 10
  Top Layer w0.5: D7_30.1@121.35,-160 D6_30.2@121.35,-150
NetD6_31_2: D6_31.2 D7_31.1 | length 10
  Top Layer w0.5: D7_31.1@141.35,-160 D6_31.2@141.35,-150
NetD6_32_2: D6_32.2 D7_32.1 | length 10
  Top Layer w0.5: D7_32.1@161.35,-160 D6_32.2@161.35,-150
NetD6_33_2: D6_33.2 D7_33.1 | length 10
  Top Layer w0.5: D7_33.1@181.35,-40 D6_33.2@181.35,-30
NetD6_34_2: D6_34.2 D7_34.1 | length 10
  Top Layer w0.5: D7_34.1@181.35,-80 D6_34.2@181.35,-70
NetD6_35_2: D6_35.2 D7_35.1 | length 10
  Top Layer w0.5: D7_35.1@181.35,-120 D6_35.2@181.35,-110
NetD6_36_2: D6_36.2 D7_36.1 | length 10
  Top Layer w0.5: D7_36.1@181.35,-160 D6_36.2@181.35,-150
NetD7_1_2: D7_1.2 D8_1.1 | length 7.3
  Top Layer w0.5: D8_1.1@30,-118.65 29.996,-118.65 29.996,-111.35 D7_1.2@30,-111.35
NetD7_2_2: D7_2.2 D8_2.1 | length 7.3
  Top Layer w0.5: D8_2.1@40,-118.65 39.996,-118.65 39.996,-111.35 D7_2.2@40,-111.35
NetD7_3_2: D7_3.2 D8_3.1 | length 7.3
  Top Layer w0.5: D8_3.1@50,-118.65 49.996,-118.65 49.996,-111.35 D7_3.2@50,-111.35
NetD7_4_2: D7_4.2 D8_4.1 | length 7.3
  Top Layer w0.5: D8_4.1@60,-118.65 59.996,-118.65 59.996,-111.35 D7_4.2@60,-111.35
NetD7_5_2: D7_5.2 D8_5.1 | length 7.3
  Top Layer w0.5: D8_5.1@70,-118.65 69.996,-118.65 69.996,-111.35 D7_5.2@70,-111.35
NetD7_6_2: D7_6.2 D8_6.1 | length 7.3
  Top Layer w0.5: D8_6.1@80,-118.65 79.996,-118.65 79.996,-111.35 D7_6.2@80,-111.35
NetD7_7_2: D7_7.2 D8_7.1 | length 7.3
  Top Layer w0.5: D8_7.1@90,-118.65 89.996,-118.65 89.996,-111.35 D7_7.2@90,-111.35
NetD7_8_2: D7_8.2 D8_8.1 | length 7.3
  Top Layer w0.5: D8_8.1@100,-118.65 99.996,-118.65 99.996,-111.35 D7_8.2@100,-111.35
NetD7_9_2: D7_9.2 D8_9.1 | length 7.3
  Top Layer w0.5: D8_9.1@110,-118.65 109.996,-118.65 109.996,-111.35 D7_9.2@110,-111.35
NetD7_10_2: D7_10.2 D8_10.1 | length 7.3
  Top Layer w0.5: D8_10.1@120,-118.65 119.996,-118.65 119.996,-111.35 D7_10.2@120,-111.35
NetD7_11_2: D7_11.2 D8_11.1 | length 7.3
  Top Layer w0.5: D8_11.1@130,-118.65 129.996,-118.65 129.996,-111.35 D7_11.2@130,-111.35
NetD7_12_2: D7_12.2 D8_12.1 | length 7.3
  Top Layer w0.5: D8_12.1@140,-118.65 139.996,-118.65 139.996,-111.35 D7_12.2@140,-111.35
NetD7_13_2: D7_13.2 D8_13.1 | length 7.3
  Top Layer w0.5: D8_13.1@150,-118.65 149.996,-118.65 149.996,-111.35 D7_13.2@150,-111.35
NetD7_14_2: D7_14.2 D8_14.1 | length 7.3
  Top Layer w0.5: D8_14.1@160,-118.65 159.996,-118.65 159.996,-111.35 D7_14.2@160,-111.35
NetD7_15_2: D7_15.2 D8_15.1 | length 7.3
  Top Layer w0.5: D8_15.1@11.35,-40 11.35,-39.998 18.65,-39.998 D7_15.2@18.65,-40
NetD7_16_2: D7_16.2 D8_16.1 | length 7.3
  Top Layer w0.5: D8_16.1@11.35,-80 11.35,-79.998 18.65,-79.998 D7_16.2@18.65,-80
NetD7_17_2: D7_17.2 D8_17.1 | length 7.3
  Top Layer w0.5: D8_17.1@11.35,-120 11.35,-119.998 18.65,-119.998 D7_17.2@18.65,-120
NetD7_18_2: D7_18.2 D8_18.1 | length 7.3
  Top Layer w0.5: D8_18.1@11.35,-160 11.35,-159.998 18.65,-159.998 D7_18.2@18.65,-160
NetD7_19_2: D7_19.2 D8_19.1 | length 7.3
  Top Layer w0.5: D8_19.1@31.35,-40 31.35,-39.998 38.65,-39.998 D7_19.2@38.65,-40
NetD7_20_2: D7_20.2 D8_20.1 | length 7.3
  Top Layer w0.5: D8_20.1@51.35,-40 51.35,-39.998 58.65,-39.998 D7_20.2@58.65,-40
NetD7_21_2: D7_21.2 D8_21.1 | length 7.3
  Top Layer w0.5: D8_21.1@71.35,-40 71.35,-39.998 78.65,-39.998 D7_21.2@78.65,-40
NetD7_22_2: D7_22.2 D8_22.1 | length 7.3
  Top Layer w0.5: D8_22.1@91.35,-40 91.35,-39.998 98.65,-39.998 D7_22.2@98.65,-40
NetD7_23_2: D7_23.2 D8_23.1 | length 7.3
  Top Layer w0.5: D8_23.1@111.35,-40 111.35,-39.998 118.65,-39.998 D7_23.2@118.65,-40
NetD7_24_2: D7_24.2 D8_24.1 | length 7.3
  Top Layer w0.5: D8_24.1@131.35,-40 131.35,-39.998 138.65,-39.998 D7_24.2@138.65,-40
NetD7_25_2: D7_25.2 D8_25.1 | length 7.3
  Top Layer w0.5: D8_25.1@151.35,-40 151.35,-39.998 158.65,-39.998 D7_25.2@158.65,-40
NetD7_26_2: D7_26.2 D8_26.1 | length 7.3
  Top Layer w0.5: D8_26.1@31.35,-160 31.35,-159.998 38.65,-159.998 D7_26.2@38.65,-160
NetD7_27_2: D7_27.2 D8_27.1 | length 7.3
  Top Layer w0.5: D8_27.1@51.35,-160 51.35,-159.998 58.65,-159.998 D7_27.2@58.65,-160
NetD7_28_2: D7_28.2 D8_28.1 | length 7.3
  Top Layer w0.5: D8_28.1@71.35,-160 71.35,-159.998 78.65,-159.998 D7_28.2@78.65,-160
NetD7_29_2: D7_29.2 D8_29.1 | length 7.3
  Top Layer w0.5: D8_29.1@91.35,-160 91.35,-159.998 98.65,-159.998 D7_29.2@98.65,-160
NetD7_30_2: D7_30.2 D8_30.1 | length 7.3
  Top Layer w0.5: D8_30.1@111.35,-160 111.35,-159.998 118.65,-159.998 D7_30.2@118.65,-160
NetD7_31_2: D7_31.2 D8_31.1 | length 7.3
  Top Layer w0.5: D8_31.1@131.35,-160 131.35,-159.998 138.65,-159.998 D7_31.2@138.65,-160
NetD7_32_2: D7_32.2 D8_32.1 | length 7.3
  Top Layer w0.5: D8_32.1@151.35,-160 151.35,-159.998 158.65,-159.998 D7_32.2@158.65,-160
NetD7_33_2: D7_33.2 D8_33.1 | length 7.3
  Top Layer w0.5: D8_33.1@171.35,-40 171.35,-39.998 178.65,-39.998 D7_33.2@178.65,-40
NetD7_34_2: D7_34.2 D8_34.1 | length 7.3
  Top Layer w0.5: D8_34.1@171.35,-80 171.35,-79.998 178.65,-79.998 D7_34.2@178.65,-80
NetD7_35_2: D7_35.2 D8_35.1 | length 7.3
  Top Layer w0.5: D8_35.1@171.35,-120 171.35,-119.998 178.65,-119.998 D7_35.2@178.65,-120
NetD7_36_2: D7_36.2 D8_36.1 | length 7.3
  Top Layer w0.5: D8_36.1@171.35,-160 171.35,-159.998 178.65,-159.998 D7_36.2@178.65,-160
VCC_1: DR1_1.A DR1_2.A DR1_3.A DR1_4.A DR1_5.A DR1_6.A DR1_7.A DR1_8.A DR1_9.A DR1_10.A DR1_11.A DR1_12.A DR1_13.A DR1_14.A pad.2 | length 183.2
  Top Layer w0.8: DR1_1.A@32.313,-45.452 35.614,-45.452 ; DR1_2.A@36.546,-46.968 36.546,-45.555 ; DR1_3.A@46.546,-46.968 46.546,-45.555 ; DR1_4.A@56.546,-46.968 56.546,-45.555 ; DR1_5.A@66.546,-46.968 66.546,-45.555 ; DR1_6.A@76.546,-46.968 76.546,-45.555 ; DR1_7.A@86.546,-46.968 86.546,-45.555 ; DR1_8.A@96.546,-46.968 96.546,-45.555 ; DR1_9.A@106.546,-46.968 106.546,-45.555 ; DR1_10.A@116.546,-46.968 116.546,-45.555 ; DR1_11.A@126.546,-46.968 126.546,-45.555 ; DR1_12.A@136.546,-46.968 136.546,-45.555 ; DR1_13.A@146.546,-46.968 146.546,-45.555
  Top Layer w1: pad.2@33.861,-84.849 33.861,-45.555 36.546,-45.555 46.546,-45.555 56.546,-45.555 66.546,-45.555 76.546,-45.555 86.546,-45.555 96.546,-45.555 106.546,-45.555 116.546,-45.555 126.546,-45.555 136.546,-45.555 146.546,-45.555 156.202,-45.555 156.546,-45.899 DR1_14.A@156.546,-46.698
VCC_2: DR1_15.A DR1_16.A DR1_17.A DR1_18.A DR1_19.A DR1_20.A DR1_21.A DR1_22.A DR1_23.A DR1_24.A DR1_25.A DR1_26.A DR1_27.A DR1_28.A DR1_29.A DR1_30.A DR1_31.A DR1_32.A DR1_33.A DR1_34.A DR1_35.A DR1_36.A pad.4 | length 667.9
  Top Layer w0.8: DR1_16.A@6.175,-48.131 6.175,-46.088 ; DR1_15.A@6.175,-8.131 6.175,-5.911 ; DR1_26.A@26.175,-128.131 26.175,-126.225 ; DR1_19.A@26.175,-8.131 26.175,-5.911 ; DR1_27.A@46.175,-128.131 46.175,-126.225 ; DR1_20.A@46.175,-8.131 46.175,-5.911 ; DR1_28.A@66.175,-128.131 66.175,-126.225 ; DR1_21.A@66.175,-8.131 66.175,-5.911 ; DR1_29.A@86.175,-128.131 86.175,-126.225 ; DR1_22.A@86.175,-8.131 86.175,-5.911 ; DR1_30.A@106.175,-128.131 106.175,-126.225 ; DR1_23.A@106.175,-8.131 106.175,-5.911 ; DR1_31.A@126.175,-128.131 126.175,-126.225 ; DR1_24.A@126.175,-8.131 126.175,-5.911 ; DR1_32.A@146.175,-128.131 146.175,-126.225 ; DR1_25.A@146.175,-8.131 146.175,-5.911 ; DR1_34.A@166.175,-48.131 166.175,-47.175 167.338,-46.012 183.416,-46.012 ; DR1_33.A@166.175,-8.131 166.175,-5.911
  Top Layer w1: 3.584,-45.961 3.584,-6.922 4.595,-5.911 6.175,-5.911 26.175,-5.911 46.175,-5.911 66.175,-5.911 86.175,-5.911 106.175,-5.911 126.175,-5.911 146.175,-5.911 166.175,-5.911 181.212,-5.911 183.416,-8.115 183.416,-46.012 183.416,-82.08 181.968,-83.528 169.167,-83.528 166.175,-86.52 DR1_35.A@166.175,-88.131 ; 3.835,-45.857 3.686,-45.707 21.288,-45.707 23.371,-47.79 23.371,-126.225 ; DR1_18.A@6.175,-127.926 6.175,-127.064 7.013,-126.225 26.175,-126.225 46.175,-126.225 66.175,-126.225 86.175,-126.225 106.175,-126.225 126.175,-126.225 146.175,-126.225 165.357,-126.225 166.175,-127.044 DR1_36.A@166.175,-127.826 ; DR1_17.A@6.175,-88.131 6.175,-86.678 7.978,-84.874 23.091,-84.874
  Top Layer w1.5: 3.835,-45.857 3.835,-52.382 6.482,-55.029 pad.4@14.582,-55.029

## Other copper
Top Layer:
  region net VCC_2: 3.711,-44.285 3.711,-45.733 3.736,-45.758 3.838,-45.657 5.083,-45.657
